VERSION 5.7 ;
  NOWIREEXTENSIONATPIN ON ;
  DIVIDERCHAR "/" ;
  BUSBITCHARS "[]" ;
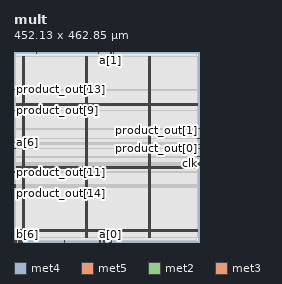
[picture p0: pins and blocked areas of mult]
MACRO mult
  CLASS BLOCK ;
  FOREIGN mult ;
  ORIGIN 0.000 0.000 ;
  SIZE 452.130 BY 462.850 ;
  PIN VGND
    DIRECTION INOUT ;
    USE GROUND ;
    PORT
      LAYER met4 ;
        RECT 24.340 10.640 25.940 451.760 ;
    END
    PORT
      LAYER met4 ;
        RECT 177.940 10.640 179.540 451.760 ;
    END
    PORT
      LAYER met4 ;
        RECT 331.540 10.640 333.140 451.760 ;
    END
    PORT
      LAYER met5 ;
        RECT 5.280 30.030 446.440 31.630 ;
    END
    PORT
      LAYER met5 ;
        RECT 5.280 183.210 446.440 184.810 ;
    END
    PORT
      LAYER met5 ;
        RECT 5.280 336.390 446.440 337.990 ;
    END
  END VGND
  PIN VPWR
    DIRECTION INOUT ;
    USE POWER ;
    PORT
      LAYER met4 ;
        RECT 21.040 10.640 22.640 451.760 ;
    END
    PORT
      LAYER met4 ;
        RECT 174.640 10.640 176.240 451.760 ;
    END
    PORT
      LAYER met4 ;
        RECT 328.240 10.640 329.840 451.760 ;
    END
    PORT
      LAYER met5 ;
        RECT 5.280 26.730 446.440 28.330 ;
    END
    PORT
      LAYER met5 ;
        RECT 5.280 179.910 446.440 181.510 ;
    END
    PORT
      LAYER met5 ;
        RECT 5.280 333.090 446.440 334.690 ;
    END
  END VPWR
  PIN a[0]
    DIRECTION INPUT ;
    USE SIGNAL ;
    ANTENNAGATEAREA 0.126000 ;
    PORT
      LAYER met2 ;
        RECT 235.150 0.000 235.430 4.000 ;
    END
  END a[0]
  PIN a[1]
    DIRECTION INPUT ;
    USE SIGNAL ;
    ANTENNAGATEAREA 0.126000 ;
    PORT
      LAYER met2 ;
        RECT 235.150 458.850 235.430 462.850 ;
    END
  END a[1]
  PIN a[2]
    DIRECTION INPUT ;
    USE SIGNAL ;
    ANTENNAGATEAREA 0.126000 ;
    PORT
      LAYER met2 ;
        RECT 219.050 0.000 219.330 4.000 ;
    END
  END a[2]
  PIN a[3]
    DIRECTION INPUT ;
    USE SIGNAL ;
    ANTENNAGATEAREA 0.196500 ;
    PORT
      LAYER met2 ;
        RECT 241.590 458.850 241.870 462.850 ;
    END
  END a[3]
  PIN a[4]
    DIRECTION INPUT ;
    USE SIGNAL ;
    ANTENNAGATEAREA 0.196500 ;
    PORT
      LAYER met2 ;
        RECT 209.390 0.000 209.670 4.000 ;
    END
  END a[4]
  PIN a[5]
    DIRECTION INPUT ;
    USE SIGNAL ;
    ANTENNAGATEAREA 0.196500 ;
    PORT
      LAYER met2 ;
        RECT 206.170 458.850 206.450 462.850 ;
    END
  END a[5]
  PIN a[6]
    DIRECTION INPUT ;
    USE SIGNAL ;
    ANTENNAGATEAREA 0.213000 ;
    PORT
      LAYER met3 ;
        RECT 0.000 241.440 4.000 242.040 ;
    END
  END a[6]
  PIN a[7]
    DIRECTION INPUT ;
    USE SIGNAL ;
    ANTENNAGATEAREA 0.196500 ;
    PORT
      LAYER met2 ;
        RECT 238.370 0.000 238.650 4.000 ;
    END
  END a[7]
  PIN b[0]
    DIRECTION INPUT ;
    USE SIGNAL ;
    ANTENNAGATEAREA 0.213000 ;
    PORT
      LAYER met3 ;
        RECT 0.000 227.840 4.000 228.440 ;
    END
  END b[0]
  PIN b[1]
    DIRECTION INPUT ;
    USE SIGNAL ;
    PORT
      LAYER met2 ;
        RECT 0.090 0.000 0.370 4.000 ;
    END
  END b[1]
  PIN b[2]
    DIRECTION INPUT ;
    USE SIGNAL ;
    PORT
      LAYER met2 ;
        RECT 3.310 0.000 3.590 4.000 ;
    END
  END b[2]
  PIN b[3]
    DIRECTION INPUT ;
    USE SIGNAL ;
    PORT
      LAYER met2 ;
        RECT 6.530 0.000 6.810 4.000 ;
    END
  END b[3]
  PIN b[4]
    DIRECTION INPUT ;
    USE SIGNAL ;
    PORT
      LAYER met2 ;
        RECT 9.750 0.000 10.030 4.000 ;
    END
  END b[4]
  PIN b[5]
    DIRECTION INPUT ;
    USE SIGNAL ;
    PORT
      LAYER met2 ;
        RECT 12.970 0.000 13.250 4.000 ;
    END
  END b[5]
  PIN b[6]
    DIRECTION INPUT ;
    USE SIGNAL ;
    PORT
      LAYER met2 ;
        RECT 16.190 0.000 16.470 4.000 ;
    END
  END b[6]
  PIN b[7]
    DIRECTION INPUT ;
    USE SIGNAL ;
    PORT
      LAYER met2 ;
        RECT 19.410 0.000 19.690 4.000 ;
    END
  END b[7]
  PIN clk
    DIRECTION INPUT ;
    USE SIGNAL ;
    ANTENNAGATEAREA 1.286700 ;
    ANTENNADIFFAREA 0.434700 ;
    PORT
      LAYER met3 ;
        RECT 448.130 190.440 452.130 191.040 ;
    END
  END clk
  PIN product_out[0]
    DIRECTION OUTPUT ;
    USE SIGNAL ;
    ANTENNADIFFAREA 0.340600 ;
    PORT
      LAYER met3 ;
        RECT 448.130 207.440 452.130 208.040 ;
    END
  END product_out[0]
  PIN product_out[10]
    DIRECTION OUTPUT ;
    USE SIGNAL ;
    PORT
      LAYER met3 ;
        RECT 0.000 132.640 4.000 133.240 ;
    END
  END product_out[10]
  PIN product_out[11]
    DIRECTION OUTPUT ;
    USE SIGNAL ;
    PORT
      LAYER met3 ;
        RECT 0.000 170.040 4.000 170.640 ;
    END
  END product_out[11]
  PIN product_out[12]
    DIRECTION OUTPUT ;
    USE SIGNAL ;
    PORT
      LAYER met2 ;
        RECT 122.450 0.000 122.730 4.000 ;
    END
  END product_out[12]
  PIN product_out[13]
    DIRECTION OUTPUT ;
    USE SIGNAL ;
    PORT
      LAYER met3 ;
        RECT 0.000 370.640 4.000 371.240 ;
    END
  END product_out[13]
  PIN product_out[14]
    DIRECTION OUTPUT ;
    USE SIGNAL ;
    PORT
      LAYER met3 ;
        RECT 0.000 136.040 4.000 136.640 ;
    END
  END product_out[14]
  PIN product_out[15]
    DIRECTION OUTPUT ;
    USE SIGNAL ;
    PORT
      LAYER met2 ;
        RECT 54.830 458.850 55.110 462.850 ;
    END
  END product_out[15]
  PIN product_out[1]
    DIRECTION OUTPUT ;
    USE SIGNAL ;
    ANTENNADIFFAREA 0.340600 ;
    PORT
      LAYER met3 ;
        RECT 448.130 251.640 452.130 252.240 ;
    END
  END product_out[1]
  PIN product_out[2]
    DIRECTION OUTPUT ;
    USE SIGNAL ;
    ANTENNADIFFAREA 0.340600 ;
    PORT
      LAYER met3 ;
        RECT 448.130 227.840 452.130 228.440 ;
    END
  END product_out[2]
  PIN product_out[3]
    DIRECTION OUTPUT ;
    USE SIGNAL ;
    ANTENNADIFFAREA 0.340600 ;
    PORT
      LAYER met3 ;
        RECT 448.130 275.440 452.130 276.040 ;
    END
  END product_out[3]
  PIN product_out[4]
    DIRECTION OUTPUT ;
    USE SIGNAL ;
    ANTENNADIFFAREA 0.340600 ;
    PORT
      LAYER met2 ;
        RECT 231.930 0.000 232.210 4.000 ;
    END
  END product_out[4]
  PIN product_out[5]
    DIRECTION OUTPUT ;
    USE SIGNAL ;
    ANTENNADIFFAREA 0.340600 ;
    PORT
      LAYER met2 ;
        RECT 238.370 458.850 238.650 462.850 ;
    END
  END product_out[5]
  PIN product_out[6]
    DIRECTION OUTPUT ;
    USE SIGNAL ;
    ANTENNADIFFAREA 0.340600 ;
    PORT
      LAYER met3 ;
        RECT 448.130 238.040 452.130 238.640 ;
    END
  END product_out[6]
  PIN product_out[7]
    DIRECTION OUTPUT ;
    USE SIGNAL ;
    ANTENNADIFFAREA 0.340600 ;
    PORT
      LAYER met3 ;
        RECT 448.130 187.040 452.130 187.640 ;
    END
  END product_out[7]
  PIN product_out[8]
    DIRECTION OUTPUT ;
    USE SIGNAL ;
    PORT
      LAYER met3 ;
        RECT 0.000 139.440 4.000 140.040 ;
    END
  END product_out[8]
  PIN product_out[9]
    DIRECTION OUTPUT ;
    USE SIGNAL ;
    PORT
      LAYER met3 ;
        RECT 0.000 319.640 4.000 320.240 ;
    END
  END product_out[9]
  PIN rst
    DIRECTION INPUT ;
    USE SIGNAL ;
    ANTENNAGATEAREA 0.990000 ;
    PORT
      LAYER met3 ;
        RECT 448.130 193.840 452.130 194.440 ;
    END
  END rst
  OBS
      LAYER nwell ;
        RECT 5.330 10.795 446.390 451.605 ;
      LAYER li1 ;
        RECT 5.520 10.795 446.200 451.605 ;
      LAYER met1 ;
        RECT 4.210 10.640 446.200 451.760 ;
      LAYER met2 ;
        RECT 4.230 458.570 54.550 459.410 ;
        RECT 55.390 458.570 205.890 459.410 ;
        RECT 206.730 458.570 234.870 459.410 ;
        RECT 235.710 458.570 238.090 459.410 ;
        RECT 238.930 458.570 241.310 459.410 ;
        RECT 242.150 458.570 444.730 459.410 ;
        RECT 4.230 4.280 444.730 458.570 ;
        RECT 4.230 4.000 6.250 4.280 ;
        RECT 7.090 4.000 9.470 4.280 ;
        RECT 10.310 4.000 12.690 4.280 ;
        RECT 13.530 4.000 15.910 4.280 ;
        RECT 16.750 4.000 19.130 4.280 ;
        RECT 19.970 4.000 122.170 4.280 ;
        RECT 123.010 4.000 209.110 4.280 ;
        RECT 209.950 4.000 218.770 4.280 ;
        RECT 219.610 4.000 231.650 4.280 ;
        RECT 232.490 4.000 234.870 4.280 ;
        RECT 235.710 4.000 238.090 4.280 ;
        RECT 238.930 4.000 444.730 4.280 ;
      LAYER met3 ;
        RECT 3.990 371.640 448.130 451.685 ;
        RECT 4.400 370.240 448.130 371.640 ;
        RECT 3.990 320.640 448.130 370.240 ;
        RECT 4.400 319.240 448.130 320.640 ;
        RECT 3.990 276.440 448.130 319.240 ;
        RECT 3.990 275.040 447.730 276.440 ;
        RECT 3.990 252.640 448.130 275.040 ;
        RECT 3.990 251.240 447.730 252.640 ;
        RECT 3.990 242.440 448.130 251.240 ;
        RECT 4.400 241.040 448.130 242.440 ;
        RECT 3.990 239.040 448.130 241.040 ;
        RECT 3.990 237.640 447.730 239.040 ;
        RECT 3.990 228.840 448.130 237.640 ;
        RECT 4.400 227.440 447.730 228.840 ;
        RECT 3.990 208.440 448.130 227.440 ;
        RECT 3.990 207.040 447.730 208.440 ;
        RECT 3.990 194.840 448.130 207.040 ;
        RECT 3.990 193.440 447.730 194.840 ;
        RECT 3.990 191.440 448.130 193.440 ;
        RECT 3.990 190.040 447.730 191.440 ;
        RECT 3.990 188.040 448.130 190.040 ;
        RECT 3.990 186.640 447.730 188.040 ;
        RECT 3.990 171.040 448.130 186.640 ;
        RECT 4.400 169.640 448.130 171.040 ;
        RECT 3.990 140.440 448.130 169.640 ;
        RECT 4.400 139.040 448.130 140.440 ;
        RECT 3.990 137.040 448.130 139.040 ;
        RECT 4.400 135.640 448.130 137.040 ;
        RECT 3.990 133.640 448.130 135.640 ;
        RECT 4.400 132.240 448.130 133.640 ;
        RECT 3.990 10.715 448.130 132.240 ;
  END
END mult
END LIBRARY

